VERSION 5.7 ;
  NOWIREEXTENSIONATPIN ON ;
  DIVIDERCHAR "/" ;
  BUSBITCHARS "[]" ;
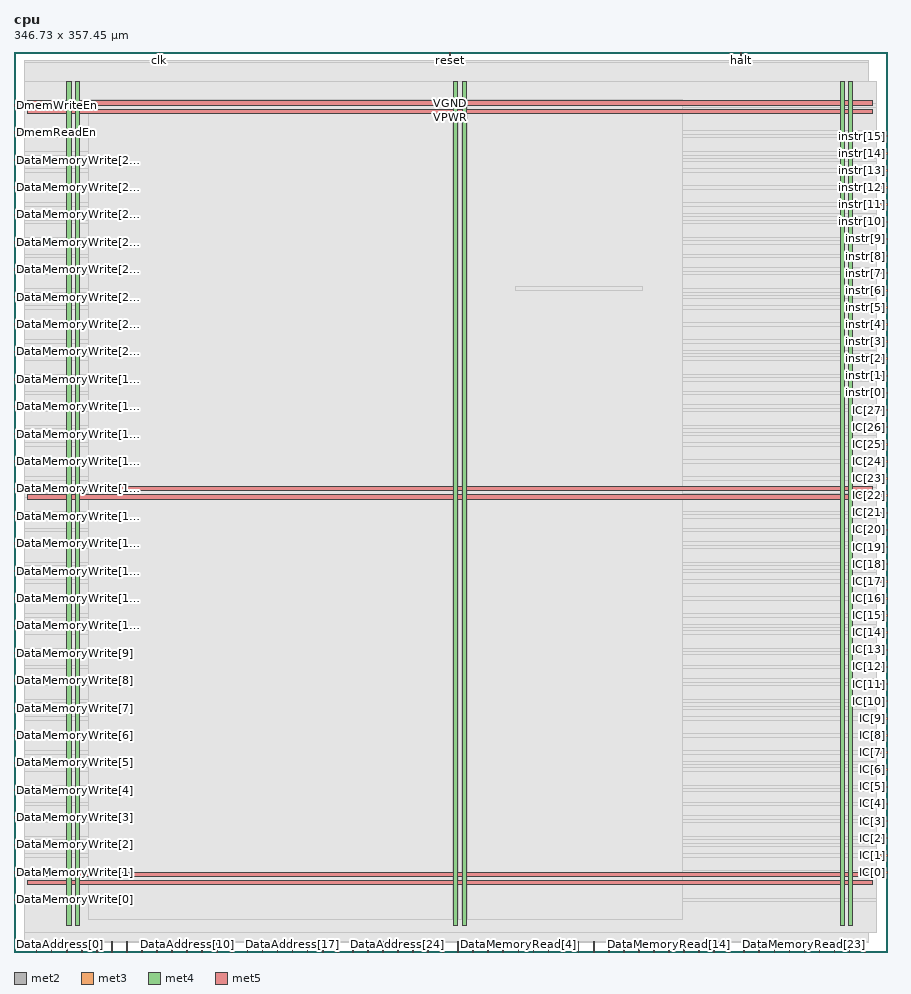
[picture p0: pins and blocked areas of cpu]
MACRO cpu
  CLASS BLOCK ;
  FOREIGN cpu ;
  ORIGIN 0.000 0.000 ;
  SIZE 346.730 BY 357.450 ;
  PIN DataAddress[0]
    DIRECTION OUTPUT ;
    USE SIGNAL ;
    ANTENNADIFFAREA 0.340600 ;
    PORT
      LAYER met2 ;
        RECT 8.830 0.000 9.110 4.000 ;
    END
  END DataAddress[0]
  PIN DataAddress[10]
    DIRECTION OUTPUT ;
    USE SIGNAL ;
    ANTENNADIFFAREA 0.340600 ;
    PORT
      LAYER met2 ;
        RECT 68.630 0.000 68.910 4.000 ;
    END
  END DataAddress[10]
  PIN DataAddress[11]
    DIRECTION OUTPUT ;
    USE SIGNAL ;
    ANTENNADIFFAREA 0.340600 ;
    PORT
      LAYER met2 ;
        RECT 74.610 0.000 74.890 4.000 ;
    END
  END DataAddress[11]
  PIN DataAddress[12]
    DIRECTION OUTPUT ;
    USE SIGNAL ;
    ANTENNADIFFAREA 0.340600 ;
    PORT
      LAYER met2 ;
        RECT 80.590 0.000 80.870 4.000 ;
    END
  END DataAddress[12]
  PIN DataAddress[13]
    DIRECTION OUTPUT ;
    USE SIGNAL ;
    ANTENNADIFFAREA 0.340600 ;
    PORT
      LAYER met2 ;
        RECT 86.570 0.000 86.850 4.000 ;
    END
  END DataAddress[13]
  PIN DataAddress[14]
    DIRECTION OUTPUT ;
    USE SIGNAL ;
    ANTENNADIFFAREA 0.340600 ;
    PORT
      LAYER met2 ;
        RECT 92.550 0.000 92.830 4.000 ;
    END
  END DataAddress[14]
  PIN DataAddress[15]
    DIRECTION OUTPUT ;
    USE SIGNAL ;
    ANTENNADIFFAREA 0.340600 ;
    PORT
      LAYER met2 ;
        RECT 98.530 0.000 98.810 4.000 ;
    END
  END DataAddress[15]
  PIN DataAddress[16]
    DIRECTION OUTPUT ;
    USE SIGNAL ;
    ANTENNADIFFAREA 0.340600 ;
    PORT
      LAYER met2 ;
        RECT 104.510 0.000 104.790 4.000 ;
    END
  END DataAddress[16]
  PIN DataAddress[17]
    DIRECTION OUTPUT ;
    USE SIGNAL ;
    ANTENNADIFFAREA 0.340600 ;
    PORT
      LAYER met2 ;
        RECT 110.490 0.000 110.770 4.000 ;
    END
  END DataAddress[17]
  PIN DataAddress[18]
    DIRECTION OUTPUT ;
    USE SIGNAL ;
    ANTENNADIFFAREA 0.340600 ;
    PORT
      LAYER met2 ;
        RECT 116.470 0.000 116.750 4.000 ;
    END
  END DataAddress[18]
  PIN DataAddress[19]
    DIRECTION OUTPUT ;
    USE SIGNAL ;
    ANTENNADIFFAREA 0.340600 ;
    PORT
      LAYER met2 ;
        RECT 122.450 0.000 122.730 4.000 ;
    END
  END DataAddress[19]
  PIN DataAddress[1]
    DIRECTION OUTPUT ;
    USE SIGNAL ;
    ANTENNADIFFAREA 0.340600 ;
    PORT
      LAYER met2 ;
        RECT 14.810 0.000 15.090 4.000 ;
    END
  END DataAddress[1]
  PIN DataAddress[20]
    DIRECTION OUTPUT ;
    USE SIGNAL ;
    ANTENNADIFFAREA 0.340600 ;
    PORT
      LAYER met2 ;
        RECT 128.430 0.000 128.710 4.000 ;
    END
  END DataAddress[20]
  PIN DataAddress[21]
    DIRECTION OUTPUT ;
    USE SIGNAL ;
    ANTENNADIFFAREA 0.340600 ;
    PORT
      LAYER met2 ;
        RECT 134.410 0.000 134.690 4.000 ;
    END
  END DataAddress[21]
  PIN DataAddress[22]
    DIRECTION OUTPUT ;
    USE SIGNAL ;
    ANTENNADIFFAREA 0.340600 ;
    PORT
      LAYER met2 ;
        RECT 140.390 0.000 140.670 4.000 ;
    END
  END DataAddress[22]
  PIN DataAddress[23]
    DIRECTION OUTPUT ;
    USE SIGNAL ;
    ANTENNADIFFAREA 0.340600 ;
    PORT
      LAYER met2 ;
        RECT 146.370 0.000 146.650 4.000 ;
    END
  END DataAddress[23]
  PIN DataAddress[24]
    DIRECTION OUTPUT ;
    USE SIGNAL ;
    ANTENNADIFFAREA 0.340600 ;
    PORT
      LAYER met2 ;
        RECT 152.350 0.000 152.630 4.000 ;
    END
  END DataAddress[24]
  PIN DataAddress[25]
    DIRECTION OUTPUT ;
    USE SIGNAL ;
    ANTENNADIFFAREA 0.340600 ;
    PORT
      LAYER met2 ;
        RECT 158.330 0.000 158.610 4.000 ;
    END
  END DataAddress[25]
  PIN DataAddress[26]
    DIRECTION OUTPUT ;
    USE SIGNAL ;
    ANTENNADIFFAREA 0.340600 ;
    PORT
      LAYER met2 ;
        RECT 164.310 0.000 164.590 4.000 ;
    END
  END DataAddress[26]
  PIN DataAddress[27]
    DIRECTION OUTPUT ;
    USE SIGNAL ;
    ANTENNADIFFAREA 0.340600 ;
    PORT
      LAYER met2 ;
        RECT 170.290 0.000 170.570 4.000 ;
    END
  END DataAddress[27]
  PIN DataAddress[2]
    DIRECTION OUTPUT ;
    USE SIGNAL ;
    ANTENNADIFFAREA 0.340600 ;
    PORT
      LAYER met2 ;
        RECT 20.790 0.000 21.070 4.000 ;
    END
  END DataAddress[2]
  PIN DataAddress[3]
    DIRECTION OUTPUT ;
    USE SIGNAL ;
    ANTENNADIFFAREA 0.340600 ;
    PORT
      LAYER met2 ;
        RECT 26.770 0.000 27.050 4.000 ;
    END
  END DataAddress[3]
  PIN DataAddress[4]
    DIRECTION OUTPUT ;
    USE SIGNAL ;
    ANTENNADIFFAREA 0.340600 ;
    PORT
      LAYER met2 ;
        RECT 32.750 0.000 33.030 4.000 ;
    END
  END DataAddress[4]
  PIN DataAddress[5]
    DIRECTION OUTPUT ;
    USE SIGNAL ;
    ANTENNADIFFAREA 0.340600 ;
    PORT
      LAYER met2 ;
        RECT 38.730 0.000 39.010 4.000 ;
    END
  END DataAddress[5]
  PIN DataAddress[6]
    DIRECTION OUTPUT ;
    USE SIGNAL ;
    ANTENNADIFFAREA 0.340600 ;
    PORT
      LAYER met2 ;
        RECT 44.710 0.000 44.990 4.000 ;
    END
  END DataAddress[6]
  PIN DataAddress[7]
    DIRECTION OUTPUT ;
    USE SIGNAL ;
    ANTENNADIFFAREA 0.340600 ;
    PORT
      LAYER met2 ;
        RECT 50.690 0.000 50.970 4.000 ;
    END
  END DataAddress[7]
  PIN DataAddress[8]
    DIRECTION OUTPUT ;
    USE SIGNAL ;
    ANTENNADIFFAREA 0.340600 ;
    PORT
      LAYER met2 ;
        RECT 56.670 0.000 56.950 4.000 ;
    END
  END DataAddress[8]
  PIN DataAddress[9]
    DIRECTION OUTPUT ;
    USE SIGNAL ;
    ANTENNADIFFAREA 0.340600 ;
    PORT
      LAYER met2 ;
        RECT 62.650 0.000 62.930 4.000 ;
    END
  END DataAddress[9]
  PIN DataMemoryRead[0]
    DIRECTION INPUT ;
    USE SIGNAL ;
    ANTENNAGATEAREA 0.196500 ;
    PORT
      LAYER met2 ;
        RECT 176.270 0.000 176.550 4.000 ;
    END
  END DataMemoryRead[0]
  PIN DataMemoryRead[10]
    DIRECTION INPUT ;
    USE SIGNAL ;
    ANTENNAGATEAREA 0.196500 ;
    PORT
      LAYER met2 ;
        RECT 236.070 0.000 236.350 4.000 ;
    END
  END DataMemoryRead[10]
  PIN DataMemoryRead[11]
    DIRECTION INPUT ;
    USE SIGNAL ;
    ANTENNAGATEAREA 0.213000 ;
    PORT
      LAYER met2 ;
        RECT 242.050 0.000 242.330 4.000 ;
    END
  END DataMemoryRead[11]
  PIN DataMemoryRead[12]
    DIRECTION INPUT ;
    USE SIGNAL ;
    ANTENNAGATEAREA 0.213000 ;
    PORT
      LAYER met2 ;
        RECT 248.030 0.000 248.310 4.000 ;
    END
  END DataMemoryRead[12]
  PIN DataMemoryRead[13]
    DIRECTION INPUT ;
    USE SIGNAL ;
    ANTENNAGATEAREA 0.213000 ;
    PORT
      LAYER met2 ;
        RECT 254.010 0.000 254.290 4.000 ;
    END
  END DataMemoryRead[13]
  PIN DataMemoryRead[14]
    DIRECTION INPUT ;
    USE SIGNAL ;
    ANTENNAGATEAREA 0.213000 ;
    PORT
      LAYER met2 ;
        RECT 259.990 0.000 260.270 4.000 ;
    END
  END DataMemoryRead[14]
  PIN DataMemoryRead[15]
    DIRECTION INPUT ;
    USE SIGNAL ;
    ANTENNAGATEAREA 0.213000 ;
    PORT
      LAYER met2 ;
        RECT 265.970 0.000 266.250 4.000 ;
    END
  END DataMemoryRead[15]
  PIN DataMemoryRead[16]
    DIRECTION INPUT ;
    USE SIGNAL ;
    ANTENNAGATEAREA 0.213000 ;
    PORT
      LAYER met2 ;
        RECT 271.950 0.000 272.230 4.000 ;
    END
  END DataMemoryRead[16]
  PIN DataMemoryRead[17]
    DIRECTION INPUT ;
    USE SIGNAL ;
    ANTENNAGATEAREA 0.213000 ;
    PORT
      LAYER met2 ;
        RECT 277.930 0.000 278.210 4.000 ;
    END
  END DataMemoryRead[17]
  PIN DataMemoryRead[18]
    DIRECTION INPUT ;
    USE SIGNAL ;
    ANTENNAGATEAREA 0.213000 ;
    PORT
      LAYER met2 ;
        RECT 283.910 0.000 284.190 4.000 ;
    END
  END DataMemoryRead[18]
  PIN DataMemoryRead[19]
    DIRECTION INPUT ;
    USE SIGNAL ;
    ANTENNAGATEAREA 0.213000 ;
    PORT
      LAYER met2 ;
        RECT 289.890 0.000 290.170 4.000 ;
    END
  END DataMemoryRead[19]
  PIN DataMemoryRead[1]
    DIRECTION INPUT ;
    USE SIGNAL ;
    ANTENNAGATEAREA 0.196500 ;
    PORT
      LAYER met2 ;
        RECT 182.250 0.000 182.530 4.000 ;
    END
  END DataMemoryRead[1]
  PIN DataMemoryRead[20]
    DIRECTION INPUT ;
    USE SIGNAL ;
    ANTENNAGATEAREA 0.196500 ;
    PORT
      LAYER met2 ;
        RECT 295.870 0.000 296.150 4.000 ;
    END
  END DataMemoryRead[20]
  PIN DataMemoryRead[21]
    DIRECTION INPUT ;
    USE SIGNAL ;
    ANTENNAGATEAREA 0.196500 ;
    PORT
      LAYER met2 ;
        RECT 301.850 0.000 302.130 4.000 ;
    END
  END DataMemoryRead[21]
  PIN DataMemoryRead[22]
    DIRECTION INPUT ;
    USE SIGNAL ;
    ANTENNAGATEAREA 0.196500 ;
    PORT
      LAYER met2 ;
        RECT 307.830 0.000 308.110 4.000 ;
    END
  END DataMemoryRead[22]
  PIN DataMemoryRead[23]
    DIRECTION INPUT ;
    USE SIGNAL ;
    ANTENNAGATEAREA 0.196500 ;
    PORT
      LAYER met2 ;
        RECT 313.810 0.000 314.090 4.000 ;
    END
  END DataMemoryRead[23]
  PIN DataMemoryRead[24]
    DIRECTION INPUT ;
    USE SIGNAL ;
    ANTENNAGATEAREA 0.196500 ;
    PORT
      LAYER met2 ;
        RECT 319.790 0.000 320.070 4.000 ;
    END
  END DataMemoryRead[24]
  PIN DataMemoryRead[25]
    DIRECTION INPUT ;
    USE SIGNAL ;
    ANTENNAGATEAREA 0.126000 ;
    PORT
      LAYER met2 ;
        RECT 325.770 0.000 326.050 4.000 ;
    END
  END DataMemoryRead[25]
  PIN DataMemoryRead[26]
    DIRECTION INPUT ;
    USE SIGNAL ;
    ANTENNAGATEAREA 0.213000 ;
    PORT
      LAYER met2 ;
        RECT 331.750 0.000 332.030 4.000 ;
    END
  END DataMemoryRead[26]
  PIN DataMemoryRead[27]
    DIRECTION INPUT ;
    USE SIGNAL ;
    ANTENNAGATEAREA 0.126000 ;
    PORT
      LAYER met2 ;
        RECT 337.730 0.000 338.010 4.000 ;
    END
  END DataMemoryRead[27]
  PIN DataMemoryRead[2]
    DIRECTION INPUT ;
    USE SIGNAL ;
    ANTENNAGATEAREA 0.196500 ;
    PORT
      LAYER met2 ;
        RECT 188.230 0.000 188.510 4.000 ;
    END
  END DataMemoryRead[2]
  PIN DataMemoryRead[3]
    DIRECTION INPUT ;
    USE SIGNAL ;
    ANTENNAGATEAREA 0.196500 ;
    PORT
      LAYER met2 ;
        RECT 194.210 0.000 194.490 4.000 ;
    END
  END DataMemoryRead[3]
  PIN DataMemoryRead[4]
    DIRECTION INPUT ;
    USE SIGNAL ;
    ANTENNAGATEAREA 0.196500 ;
    PORT
      LAYER met2 ;
        RECT 200.190 0.000 200.470 4.000 ;
    END
  END DataMemoryRead[4]
  PIN DataMemoryRead[5]
    DIRECTION INPUT ;
    USE SIGNAL ;
    ANTENNAGATEAREA 0.196500 ;
    PORT
      LAYER met2 ;
        RECT 206.170 0.000 206.450 4.000 ;
    END
  END DataMemoryRead[5]
  PIN DataMemoryRead[6]
    DIRECTION INPUT ;
    USE SIGNAL ;
    ANTENNAGATEAREA 0.196500 ;
    PORT
      LAYER met2 ;
        RECT 212.150 0.000 212.430 4.000 ;
    END
  END DataMemoryRead[6]
  PIN DataMemoryRead[7]
    DIRECTION INPUT ;
    USE SIGNAL ;
    ANTENNAGATEAREA 0.196500 ;
    PORT
      LAYER met2 ;
        RECT 218.130 0.000 218.410 4.000 ;
    END
  END DataMemoryRead[7]
  PIN DataMemoryRead[8]
    DIRECTION INPUT ;
    USE SIGNAL ;
    ANTENNAGATEAREA 0.196500 ;
    PORT
      LAYER met2 ;
        RECT 224.110 0.000 224.390 4.000 ;
    END
  END DataMemoryRead[8]
  PIN DataMemoryRead[9]
    DIRECTION INPUT ;
    USE SIGNAL ;
    ANTENNAGATEAREA 0.196500 ;
    PORT
      LAYER met2 ;
        RECT 230.090 0.000 230.370 4.000 ;
    END
  END DataMemoryRead[9]
  PIN DataMemoryWrite[0]
    DIRECTION OUTPUT ;
    USE SIGNAL ;
    ANTENNADIFFAREA 0.340600 ;
    PORT
      LAYER met3 ;
        RECT 0.000 20.440 4.000 21.040 ;
    END
  END DataMemoryWrite[0]
  PIN DataMemoryWrite[10]
    DIRECTION OUTPUT ;
    USE SIGNAL ;
    ANTENNADIFFAREA 0.340600 ;
    PORT
      LAYER met3 ;
        RECT 0.000 129.240 4.000 129.840 ;
    END
  END DataMemoryWrite[10]
  PIN DataMemoryWrite[11]
    DIRECTION OUTPUT ;
    USE SIGNAL ;
    ANTENNADIFFAREA 0.340600 ;
    PORT
      LAYER met3 ;
        RECT 0.000 140.120 4.000 140.720 ;
    END
  END DataMemoryWrite[11]
  PIN DataMemoryWrite[12]
    DIRECTION OUTPUT ;
    USE SIGNAL ;
    ANTENNADIFFAREA 0.340600 ;
    PORT
      LAYER met3 ;
        RECT 0.000 151.000 4.000 151.600 ;
    END
  END DataMemoryWrite[12]
  PIN DataMemoryWrite[13]
    DIRECTION OUTPUT ;
    USE SIGNAL ;
    ANTENNADIFFAREA 0.340600 ;
    PORT
      LAYER met3 ;
        RECT 0.000 161.880 4.000 162.480 ;
    END
  END DataMemoryWrite[13]
  PIN DataMemoryWrite[14]
    DIRECTION OUTPUT ;
    USE SIGNAL ;
    ANTENNADIFFAREA 0.340600 ;
    PORT
      LAYER met3 ;
        RECT 0.000 172.760 4.000 173.360 ;
    END
  END DataMemoryWrite[14]
  PIN DataMemoryWrite[15]
    DIRECTION OUTPUT ;
    USE SIGNAL ;
    ANTENNADIFFAREA 0.340600 ;
    PORT
      LAYER met3 ;
        RECT 0.000 183.640 4.000 184.240 ;
    END
  END DataMemoryWrite[15]
  PIN DataMemoryWrite[16]
    DIRECTION OUTPUT ;
    USE SIGNAL ;
    ANTENNADIFFAREA 0.340600 ;
    PORT
      LAYER met3 ;
        RECT 0.000 194.520 4.000 195.120 ;
    END
  END DataMemoryWrite[16]
  PIN DataMemoryWrite[17]
    DIRECTION OUTPUT ;
    USE SIGNAL ;
    ANTENNADIFFAREA 0.340600 ;
    PORT
      LAYER met3 ;
        RECT 0.000 205.400 4.000 206.000 ;
    END
  END DataMemoryWrite[17]
  PIN DataMemoryWrite[18]
    DIRECTION OUTPUT ;
    USE SIGNAL ;
    ANTENNADIFFAREA 0.340600 ;
    PORT
      LAYER met3 ;
        RECT 0.000 216.280 4.000 216.880 ;
    END
  END DataMemoryWrite[18]
  PIN DataMemoryWrite[19]
    DIRECTION OUTPUT ;
    USE SIGNAL ;
    ANTENNADIFFAREA 0.340600 ;
    PORT
      LAYER met3 ;
        RECT 0.000 227.160 4.000 227.760 ;
    END
  END DataMemoryWrite[19]
  PIN DataMemoryWrite[1]
    DIRECTION OUTPUT ;
    USE SIGNAL ;
    ANTENNADIFFAREA 0.340600 ;
    PORT
      LAYER met3 ;
        RECT 0.000 31.320 4.000 31.920 ;
    END
  END DataMemoryWrite[1]
  PIN DataMemoryWrite[20]
    DIRECTION OUTPUT ;
    USE SIGNAL ;
    ANTENNADIFFAREA 0.340600 ;
    PORT
      LAYER met3 ;
        RECT 0.000 238.040 4.000 238.640 ;
    END
  END DataMemoryWrite[20]
  PIN DataMemoryWrite[21]
    DIRECTION OUTPUT ;
    USE SIGNAL ;
    ANTENNADIFFAREA 0.340600 ;
    PORT
      LAYER met3 ;
        RECT 0.000 248.920 4.000 249.520 ;
    END
  END DataMemoryWrite[21]
  PIN DataMemoryWrite[22]
    DIRECTION OUTPUT ;
    USE SIGNAL ;
    ANTENNADIFFAREA 0.340600 ;
    PORT
      LAYER met3 ;
        RECT 0.000 259.800 4.000 260.400 ;
    END
  END DataMemoryWrite[22]
  PIN DataMemoryWrite[23]
    DIRECTION OUTPUT ;
    USE SIGNAL ;
    ANTENNADIFFAREA 0.340600 ;
    PORT
      LAYER met3 ;
        RECT 0.000 270.680 4.000 271.280 ;
    END
  END DataMemoryWrite[23]
  PIN DataMemoryWrite[24]
    DIRECTION OUTPUT ;
    USE SIGNAL ;
    ANTENNADIFFAREA 0.340600 ;
    PORT
      LAYER met3 ;
        RECT 0.000 281.560 4.000 282.160 ;
    END
  END DataMemoryWrite[24]
  PIN DataMemoryWrite[25]
    DIRECTION OUTPUT ;
    USE SIGNAL ;
    ANTENNADIFFAREA 0.340600 ;
    PORT
      LAYER met3 ;
        RECT 0.000 292.440 4.000 293.040 ;
    END
  END DataMemoryWrite[25]
  PIN DataMemoryWrite[26]
    DIRECTION OUTPUT ;
    USE SIGNAL ;
    ANTENNADIFFAREA 0.340600 ;
    PORT
      LAYER met3 ;
        RECT 0.000 303.320 4.000 303.920 ;
    END
  END DataMemoryWrite[26]
  PIN DataMemoryWrite[27]
    DIRECTION OUTPUT ;
    USE SIGNAL ;
    ANTENNADIFFAREA 0.340600 ;
    PORT
      LAYER met3 ;
        RECT 0.000 314.200 4.000 314.800 ;
    END
  END DataMemoryWrite[27]
  PIN DataMemoryWrite[2]
    DIRECTION OUTPUT ;
    USE SIGNAL ;
    ANTENNADIFFAREA 0.340600 ;
    PORT
      LAYER met3 ;
        RECT 0.000 42.200 4.000 42.800 ;
    END
  END DataMemoryWrite[2]
  PIN DataMemoryWrite[3]
    DIRECTION OUTPUT ;
    USE SIGNAL ;
    ANTENNADIFFAREA 0.340600 ;
    PORT
      LAYER met3 ;
        RECT 0.000 53.080 4.000 53.680 ;
    END
  END DataMemoryWrite[3]
  PIN DataMemoryWrite[4]
    DIRECTION OUTPUT ;
    USE SIGNAL ;
    ANTENNADIFFAREA 0.340600 ;
    PORT
      LAYER met3 ;
        RECT 0.000 63.960 4.000 64.560 ;
    END
  END DataMemoryWrite[4]
  PIN DataMemoryWrite[5]
    DIRECTION OUTPUT ;
    USE SIGNAL ;
    ANTENNADIFFAREA 0.340600 ;
    PORT
      LAYER met3 ;
        RECT 0.000 74.840 4.000 75.440 ;
    END
  END DataMemoryWrite[5]
  PIN DataMemoryWrite[6]
    DIRECTION OUTPUT ;
    USE SIGNAL ;
    ANTENNADIFFAREA 0.340600 ;
    PORT
      LAYER met3 ;
        RECT 0.000 85.720 4.000 86.320 ;
    END
  END DataMemoryWrite[6]
  PIN DataMemoryWrite[7]
    DIRECTION OUTPUT ;
    USE SIGNAL ;
    ANTENNADIFFAREA 0.340600 ;
    PORT
      LAYER met3 ;
        RECT 0.000 96.600 4.000 97.200 ;
    END
  END DataMemoryWrite[7]
  PIN DataMemoryWrite[8]
    DIRECTION OUTPUT ;
    USE SIGNAL ;
    ANTENNADIFFAREA 0.340600 ;
    PORT
      LAYER met3 ;
        RECT 0.000 107.480 4.000 108.080 ;
    END
  END DataMemoryWrite[8]
  PIN DataMemoryWrite[9]
    DIRECTION OUTPUT ;
    USE SIGNAL ;
    ANTENNADIFFAREA 0.340600 ;
    PORT
      LAYER met3 ;
        RECT 0.000 118.360 4.000 118.960 ;
    END
  END DataMemoryWrite[9]
  PIN DmemReadEn
    DIRECTION OUTPUT ;
    USE SIGNAL ;
    ANTENNADIFFAREA 0.340600 ;
    PORT
      LAYER met3 ;
        RECT 0.000 325.080 4.000 325.680 ;
    END
  END DmemReadEn
  PIN DmemWriteEn
    DIRECTION OUTPUT ;
    USE SIGNAL ;
    ANTENNADIFFAREA 0.340600 ;
    PORT
      LAYER met3 ;
        RECT 0.000 335.960 4.000 336.560 ;
    END
  END DmemWriteEn
  PIN IC[0]
    DIRECTION OUTPUT ;
    USE SIGNAL ;
    PORT
      LAYER met3 ;
        RECT 342.730 31.320 346.730 31.920 ;
    END
  END IC[0]
  PIN IC[10]
    DIRECTION OUTPUT ;
    USE SIGNAL ;
    ANTENNADIFFAREA 0.340600 ;
    PORT
      LAYER met3 ;
        RECT 342.730 99.320 346.730 99.920 ;
    END
  END IC[10]
  PIN IC[11]
    DIRECTION OUTPUT ;
    USE SIGNAL ;
    ANTENNADIFFAREA 0.340600 ;
    PORT
      LAYER met3 ;
        RECT 342.730 106.120 346.730 106.720 ;
    END
  END IC[11]
  PIN IC[12]
    DIRECTION OUTPUT ;
    USE SIGNAL ;
    ANTENNADIFFAREA 0.340600 ;
    PORT
      LAYER met3 ;
        RECT 342.730 112.920 346.730 113.520 ;
    END
  END IC[12]
  PIN IC[13]
    DIRECTION OUTPUT ;
    USE SIGNAL ;
    ANTENNADIFFAREA 0.340600 ;
    PORT
      LAYER met3 ;
        RECT 342.730 119.720 346.730 120.320 ;
    END
  END IC[13]
  PIN IC[14]
    DIRECTION OUTPUT ;
    USE SIGNAL ;
    ANTENNADIFFAREA 0.340600 ;
    PORT
      LAYER met3 ;
        RECT 342.730 126.520 346.730 127.120 ;
    END
  END IC[14]
  PIN IC[15]
    DIRECTION OUTPUT ;
    USE SIGNAL ;
    ANTENNADIFFAREA 0.340600 ;
    PORT
      LAYER met3 ;
        RECT 342.730 133.320 346.730 133.920 ;
    END
  END IC[15]
  PIN IC[16]
    DIRECTION OUTPUT ;
    USE SIGNAL ;
    ANTENNADIFFAREA 0.340600 ;
    PORT
      LAYER met3 ;
        RECT 342.730 140.120 346.730 140.720 ;
    END
  END IC[16]
  PIN IC[17]
    DIRECTION OUTPUT ;
    USE SIGNAL ;
    ANTENNADIFFAREA 0.340600 ;
    PORT
      LAYER met3 ;
        RECT 342.730 146.920 346.730 147.520 ;
    END
  END IC[17]
  PIN IC[18]
    DIRECTION OUTPUT ;
    USE SIGNAL ;
    ANTENNADIFFAREA 0.340600 ;
    PORT
      LAYER met3 ;
        RECT 342.730 153.720 346.730 154.320 ;
    END
  END IC[18]
  PIN IC[19]
    DIRECTION OUTPUT ;
    USE SIGNAL ;
    ANTENNADIFFAREA 0.340600 ;
    PORT
      LAYER met3 ;
        RECT 342.730 160.520 346.730 161.120 ;
    END
  END IC[19]
  PIN IC[1]
    DIRECTION OUTPUT ;
    USE SIGNAL ;
    ANTENNADIFFAREA 0.340600 ;
    PORT
      LAYER met3 ;
        RECT 342.730 38.120 346.730 38.720 ;
    END
  END IC[1]
  PIN IC[20]
    DIRECTION OUTPUT ;
    USE SIGNAL ;
    ANTENNADIFFAREA 0.340600 ;
    PORT
      LAYER met3 ;
        RECT 342.730 167.320 346.730 167.920 ;
    END
  END IC[20]
  PIN IC[21]
    DIRECTION OUTPUT ;
    USE SIGNAL ;
    ANTENNADIFFAREA 0.340600 ;
    PORT
      LAYER met3 ;
        RECT 342.730 174.120 346.730 174.720 ;
    END
  END IC[21]
  PIN IC[22]
    DIRECTION OUTPUT ;
    USE SIGNAL ;
    ANTENNADIFFAREA 0.340600 ;
    PORT
      LAYER met3 ;
        RECT 342.730 180.920 346.730 181.520 ;
    END
  END IC[22]
  PIN IC[23]
    DIRECTION OUTPUT ;
    USE SIGNAL ;
    ANTENNADIFFAREA 0.340600 ;
    PORT
      LAYER met3 ;
        RECT 342.730 187.720 346.730 188.320 ;
    END
  END IC[23]
  PIN IC[24]
    DIRECTION OUTPUT ;
    USE SIGNAL ;
    ANTENNADIFFAREA 0.340600 ;
    PORT
      LAYER met3 ;
        RECT 342.730 194.520 346.730 195.120 ;
    END
  END IC[24]
  PIN IC[25]
    DIRECTION OUTPUT ;
    USE SIGNAL ;
    ANTENNADIFFAREA 0.340600 ;
    PORT
      LAYER met3 ;
        RECT 342.730 201.320 346.730 201.920 ;
    END
  END IC[25]
  PIN IC[26]
    DIRECTION OUTPUT ;
    USE SIGNAL ;
    ANTENNADIFFAREA 0.340600 ;
    PORT
      LAYER met3 ;
        RECT 342.730 208.120 346.730 208.720 ;
    END
  END IC[26]
  PIN IC[27]
    DIRECTION OUTPUT ;
    USE SIGNAL ;
    ANTENNADIFFAREA 0.340600 ;
    PORT
      LAYER met3 ;
        RECT 342.730 214.920 346.730 215.520 ;
    END
  END IC[27]
  PIN IC[2]
    DIRECTION OUTPUT ;
    USE SIGNAL ;
    ANTENNADIFFAREA 0.340600 ;
    PORT
      LAYER met3 ;
        RECT 342.730 44.920 346.730 45.520 ;
    END
  END IC[2]
  PIN IC[3]
    DIRECTION OUTPUT ;
    USE SIGNAL ;
    ANTENNADIFFAREA 0.340600 ;
    PORT
      LAYER met3 ;
        RECT 342.730 51.720 346.730 52.320 ;
    END
  END IC[3]
  PIN IC[4]
    DIRECTION OUTPUT ;
    USE SIGNAL ;
    ANTENNADIFFAREA 0.340600 ;
    PORT
      LAYER met3 ;
        RECT 342.730 58.520 346.730 59.120 ;
    END
  END IC[4]
  PIN IC[5]
    DIRECTION OUTPUT ;
    USE SIGNAL ;
    ANTENNADIFFAREA 0.340600 ;
    PORT
      LAYER met3 ;
        RECT 342.730 65.320 346.730 65.920 ;
    END
  END IC[5]
  PIN IC[6]
    DIRECTION OUTPUT ;
    USE SIGNAL ;
    ANTENNADIFFAREA 0.340600 ;
    PORT
      LAYER met3 ;
        RECT 342.730 72.120 346.730 72.720 ;
    END
  END IC[6]
  PIN IC[7]
    DIRECTION OUTPUT ;
    USE SIGNAL ;
    ANTENNADIFFAREA 0.340600 ;
    PORT
      LAYER met3 ;
        RECT 342.730 78.920 346.730 79.520 ;
    END
  END IC[7]
  PIN IC[8]
    DIRECTION OUTPUT ;
    USE SIGNAL ;
    ANTENNADIFFAREA 0.340600 ;
    PORT
      LAYER met3 ;
        RECT 342.730 85.720 346.730 86.320 ;
    END
  END IC[8]
  PIN IC[9]
    DIRECTION OUTPUT ;
    USE SIGNAL ;
    ANTENNADIFFAREA 0.340600 ;
    PORT
      LAYER met3 ;
        RECT 342.730 92.520 346.730 93.120 ;
    END
  END IC[9]
  PIN VGND
    DIRECTION INOUT ;
    USE GROUND ;
    PORT
      LAYER met4 ;
        RECT 24.340 10.640 25.940 345.680 ;
    END
    PORT
      LAYER met4 ;
        RECT 177.940 10.640 179.540 345.680 ;
    END
    PORT
      LAYER met4 ;
        RECT 331.540 10.640 333.140 345.680 ;
    END
    PORT
      LAYER met5 ;
        RECT 5.280 30.030 341.100 31.630 ;
    END
    PORT
      LAYER met5 ;
        RECT 5.280 183.210 341.100 184.810 ;
    END
    PORT
      LAYER met5 ;
        RECT 5.280 336.390 341.100 337.990 ;
    END
  END VGND
  PIN VPWR
    DIRECTION INOUT ;
    USE POWER ;
    PORT
      LAYER met4 ;
        RECT 21.040 10.640 22.640 345.680 ;
    END
    PORT
      LAYER met4 ;
        RECT 174.640 10.640 176.240 345.680 ;
    END
    PORT
      LAYER met4 ;
        RECT 328.240 10.640 329.840 345.680 ;
    END
    PORT
      LAYER met5 ;
        RECT 5.280 26.730 341.100 28.330 ;
    END
    PORT
      LAYER met5 ;
        RECT 5.280 179.910 341.100 181.510 ;
    END
    PORT
      LAYER met5 ;
        RECT 5.280 333.090 341.100 334.690 ;
    END
  END VPWR
  PIN clk
    DIRECTION INPUT ;
    USE SIGNAL ;
    ANTENNAGATEAREA 0.852000 ;
    PORT
      LAYER met2 ;
        RECT 57.590 353.450 57.870 357.450 ;
    END
  END clk
  PIN halt
    DIRECTION OUTPUT ;
    USE SIGNAL ;
    ANTENNADIFFAREA 0.340600 ;
    PORT
      LAYER met2 ;
        RECT 288.510 353.450 288.790 357.450 ;
    END
  END halt
  PIN instr[0]
    DIRECTION INPUT ;
    USE SIGNAL ;
    ANTENNAGATEAREA 0.495000 ;
    PORT
      LAYER met3 ;
        RECT 342.730 221.720 346.730 222.320 ;
    END
  END instr[0]
  PIN instr[10]
    DIRECTION INPUT ;
    USE SIGNAL ;
    ANTENNAGATEAREA 0.247500 ;
    PORT
      LAYER met3 ;
        RECT 342.730 289.720 346.730 290.320 ;
    END
  END instr[10]
  PIN instr[11]
    DIRECTION INPUT ;
    USE SIGNAL ;
    ANTENNAGATEAREA 0.213000 ;
    PORT
      LAYER met3 ;
        RECT 342.730 296.520 346.730 297.120 ;
    END
  END instr[11]
  PIN instr[12]
    DIRECTION INPUT ;
    USE SIGNAL ;
    ANTENNAGATEAREA 0.213000 ;
    PORT
      LAYER met3 ;
        RECT 342.730 303.320 346.730 303.920 ;
    END
  END instr[12]
  PIN instr[13]
    DIRECTION INPUT ;
    USE SIGNAL ;
    ANTENNAGATEAREA 0.213000 ;
    PORT
      LAYER met3 ;
        RECT 342.730 310.120 346.730 310.720 ;
    END
  END instr[13]
  PIN instr[14]
    DIRECTION INPUT ;
    USE SIGNAL ;
    ANTENNAGATEAREA 0.990000 ;
    PORT
      LAYER met3 ;
        RECT 342.730 316.920 346.730 317.520 ;
    END
  END instr[14]
  PIN instr[15]
    DIRECTION INPUT ;
    USE SIGNAL ;
    PORT
      LAYER met3 ;
        RECT 342.730 323.720 346.730 324.320 ;
    END
  END instr[15]
  PIN instr[1]
    DIRECTION INPUT ;
    USE SIGNAL ;
    ANTENNAGATEAREA 0.495000 ;
    PORT
      LAYER met3 ;
        RECT 342.730 228.520 346.730 229.120 ;
    END
  END instr[1]
  PIN instr[2]
    DIRECTION INPUT ;
    USE SIGNAL ;
    ANTENNAGATEAREA 0.426000 ;
    PORT
      LAYER met3 ;
        RECT 342.730 235.320 346.730 235.920 ;
    END
  END instr[2]
  PIN instr[3]
    DIRECTION INPUT ;
    USE SIGNAL ;
    ANTENNAGATEAREA 0.426000 ;
    PORT
      LAYER met3 ;
        RECT 342.730 242.120 346.730 242.720 ;
    END
  END instr[3]
  PIN instr[4]
    DIRECTION INPUT ;
    USE SIGNAL ;
    ANTENNAGATEAREA 0.247500 ;
    PORT
      LAYER met3 ;
        RECT 342.730 248.920 346.730 249.520 ;
    END
  END instr[4]
  PIN instr[5]
    DIRECTION INPUT ;
    USE SIGNAL ;
    ANTENNAGATEAREA 0.247500 ;
    PORT
      LAYER met3 ;
        RECT 342.730 255.720 346.730 256.320 ;
    END
  END instr[5]
  PIN instr[6]
    DIRECTION INPUT ;
    USE SIGNAL ;
    ANTENNAGATEAREA 0.426000 ;
    PORT
      LAYER met3 ;
        RECT 342.730 262.520 346.730 263.120 ;
    END
  END instr[6]
  PIN instr[7]
    DIRECTION INPUT ;
    USE SIGNAL ;
    ANTENNAGATEAREA 0.990000 ;
    PORT
      LAYER met3 ;
        RECT 342.730 269.320 346.730 269.920 ;
    END
  END instr[7]
  PIN instr[8]
    DIRECTION INPUT ;
    USE SIGNAL ;
    ANTENNAGATEAREA 0.247500 ;
    PORT
      LAYER met3 ;
        RECT 342.730 276.120 346.730 276.720 ;
    END
  END instr[8]
  PIN instr[9]
    DIRECTION INPUT ;
    USE SIGNAL ;
    ANTENNAGATEAREA 0.495000 ;
    PORT
      LAYER met3 ;
        RECT 342.730 282.920 346.730 283.520 ;
    END
  END instr[9]
  PIN reset
    DIRECTION INPUT ;
    USE SIGNAL ;
    ANTENNAGATEAREA 0.990000 ;
    PORT
      LAYER met2 ;
        RECT 173.050 353.450 173.330 357.450 ;
    END
  END reset
  OBS
      LAYER nwell ;
        RECT 5.330 10.795 341.050 345.630 ;
      LAYER li1 ;
        RECT 5.520 10.795 340.860 345.525 ;
      LAYER met1 ;
        RECT 4.210 7.860 341.160 345.680 ;
      LAYER met2 ;
        RECT 4.230 353.170 57.310 354.010 ;
        RECT 58.150 353.170 172.770 354.010 ;
        RECT 173.610 353.170 288.230 354.010 ;
        RECT 289.070 353.170 339.390 354.010 ;
        RECT 4.230 4.280 339.390 353.170 ;
        RECT 4.230 3.670 8.550 4.280 ;
        RECT 9.390 3.670 14.530 4.280 ;
        RECT 15.370 3.670 20.510 4.280 ;
        RECT 21.350 3.670 26.490 4.280 ;
        RECT 27.330 3.670 32.470 4.280 ;
        RECT 33.310 3.670 38.450 4.280 ;
        RECT 39.290 3.670 44.430 4.280 ;
        RECT 45.270 3.670 50.410 4.280 ;
        RECT 51.250 3.670 56.390 4.280 ;
        RECT 57.230 3.670 62.370 4.280 ;
        RECT 63.210 3.670 68.350 4.280 ;
        RECT 69.190 3.670 74.330 4.280 ;
        RECT 75.170 3.670 80.310 4.280 ;
        RECT 81.150 3.670 86.290 4.280 ;
        RECT 87.130 3.670 92.270 4.280 ;
        RECT 93.110 3.670 98.250 4.280 ;
        RECT 99.090 3.670 104.230 4.280 ;
        RECT 105.070 3.670 110.210 4.280 ;
        RECT 111.050 3.670 116.190 4.280 ;
        RECT 117.030 3.670 122.170 4.280 ;
        RECT 123.010 3.670 128.150 4.280 ;
        RECT 128.990 3.670 134.130 4.280 ;
        RECT 134.970 3.670 140.110 4.280 ;
        RECT 140.950 3.670 146.090 4.280 ;
        RECT 146.930 3.670 152.070 4.280 ;
        RECT 152.910 3.670 158.050 4.280 ;
        RECT 158.890 3.670 164.030 4.280 ;
        RECT 164.870 3.670 170.010 4.280 ;
        RECT 170.850 3.670 175.990 4.280 ;
        RECT 176.830 3.670 181.970 4.280 ;
        RECT 182.810 3.670 187.950 4.280 ;
        RECT 188.790 3.670 193.930 4.280 ;
        RECT 194.770 3.670 199.910 4.280 ;
        RECT 200.750 3.670 205.890 4.280 ;
        RECT 206.730 3.670 211.870 4.280 ;
        RECT 212.710 3.670 217.850 4.280 ;
        RECT 218.690 3.670 223.830 4.280 ;
        RECT 224.670 3.670 229.810 4.280 ;
        RECT 230.650 3.670 235.790 4.280 ;
        RECT 236.630 3.670 241.770 4.280 ;
        RECT 242.610 3.670 247.750 4.280 ;
        RECT 248.590 3.670 253.730 4.280 ;
        RECT 254.570 3.670 259.710 4.280 ;
        RECT 260.550 3.670 265.690 4.280 ;
        RECT 266.530 3.670 271.670 4.280 ;
        RECT 272.510 3.670 277.650 4.280 ;
        RECT 278.490 3.670 283.630 4.280 ;
        RECT 284.470 3.670 289.610 4.280 ;
        RECT 290.450 3.670 295.590 4.280 ;
        RECT 296.430 3.670 301.570 4.280 ;
        RECT 302.410 3.670 307.550 4.280 ;
        RECT 308.390 3.670 313.530 4.280 ;
        RECT 314.370 3.670 319.510 4.280 ;
        RECT 320.350 3.670 325.490 4.280 ;
        RECT 326.330 3.670 331.470 4.280 ;
        RECT 332.310 3.670 337.450 4.280 ;
        RECT 338.290 3.670 339.390 4.280 ;
      LAYER met3 ;
        RECT 3.990 336.960 342.730 345.605 ;
        RECT 4.400 335.560 342.730 336.960 ;
        RECT 3.990 326.080 342.730 335.560 ;
        RECT 4.400 324.720 342.730 326.080 ;
        RECT 4.400 324.680 342.330 324.720 ;
        RECT 3.990 323.320 342.330 324.680 ;
        RECT 3.990 317.920 342.730 323.320 ;
        RECT 3.990 316.520 342.330 317.920 ;
        RECT 3.990 315.200 342.730 316.520 ;
        RECT 4.400 313.800 342.730 315.200 ;
        RECT 3.990 311.120 342.730 313.800 ;
        RECT 3.990 309.720 342.330 311.120 ;
        RECT 3.990 304.320 342.730 309.720 ;
        RECT 4.400 302.920 342.330 304.320 ;
        RECT 3.990 297.520 342.730 302.920 ;
        RECT 3.990 296.120 342.330 297.520 ;
        RECT 3.990 293.440 342.730 296.120 ;
        RECT 4.400 292.040 342.730 293.440 ;
        RECT 3.990 290.720 342.730 292.040 ;
        RECT 3.990 289.320 342.330 290.720 ;
        RECT 3.990 283.920 342.730 289.320 ;
        RECT 3.990 282.560 342.330 283.920 ;
        RECT 4.400 282.520 342.330 282.560 ;
        RECT 4.400 281.160 342.730 282.520 ;
        RECT 3.990 277.120 342.730 281.160 ;
        RECT 3.990 275.720 342.330 277.120 ;
        RECT 3.990 271.680 342.730 275.720 ;
        RECT 4.400 270.320 342.730 271.680 ;
        RECT 4.400 270.280 342.330 270.320 ;
        RECT 3.990 268.920 342.330 270.280 ;
        RECT 3.990 263.520 342.730 268.920 ;
        RECT 3.990 262.120 342.330 263.520 ;
        RECT 3.990 260.800 342.730 262.120 ;
        RECT 4.400 259.400 342.730 260.800 ;
        RECT 3.990 256.720 342.730 259.400 ;
        RECT 3.990 255.320 342.330 256.720 ;
        RECT 3.990 249.920 342.730 255.320 ;
        RECT 4.400 248.520 342.330 249.920 ;
        RECT 3.990 243.120 342.730 248.520 ;
        RECT 3.990 241.720 342.330 243.120 ;
        RECT 3.990 239.040 342.730 241.720 ;
        RECT 4.400 237.640 342.730 239.040 ;
        RECT 3.990 236.320 342.730 237.640 ;
        RECT 3.990 234.920 342.330 236.320 ;
        RECT 3.990 229.520 342.730 234.920 ;
        RECT 3.990 228.160 342.330 229.520 ;
        RECT 4.400 228.120 342.330 228.160 ;
        RECT 4.400 226.760 342.730 228.120 ;
        RECT 3.990 222.720 342.730 226.760 ;
        RECT 3.990 221.320 342.330 222.720 ;
        RECT 3.990 217.280 342.730 221.320 ;
        RECT 4.400 215.920 342.730 217.280 ;
        RECT 4.400 215.880 342.330 215.920 ;
        RECT 3.990 214.520 342.330 215.880 ;
        RECT 3.990 209.120 342.730 214.520 ;
        RECT 3.990 207.720 342.330 209.120 ;
        RECT 3.990 206.400 342.730 207.720 ;
        RECT 4.400 205.000 342.730 206.400 ;
        RECT 3.990 202.320 342.730 205.000 ;
        RECT 3.990 200.920 342.330 202.320 ;
        RECT 3.990 195.520 342.730 200.920 ;
        RECT 4.400 194.120 342.330 195.520 ;
        RECT 3.990 188.720 342.730 194.120 ;
        RECT 3.990 187.320 342.330 188.720 ;
        RECT 3.990 184.640 342.730 187.320 ;
        RECT 4.400 183.240 342.730 184.640 ;
        RECT 3.990 181.920 342.730 183.240 ;
        RECT 3.990 180.520 342.330 181.920 ;
        RECT 3.990 175.120 342.730 180.520 ;
        RECT 3.990 173.760 342.330 175.120 ;
        RECT 4.400 173.720 342.330 173.760 ;
        RECT 4.400 172.360 342.730 173.720 ;
        RECT 3.990 168.320 342.730 172.360 ;
        RECT 3.990 166.920 342.330 168.320 ;
        RECT 3.990 162.880 342.730 166.920 ;
        RECT 4.400 161.520 342.730 162.880 ;
        RECT 4.400 161.480 342.330 161.520 ;
        RECT 3.990 160.120 342.330 161.480 ;
        RECT 3.990 154.720 342.730 160.120 ;
        RECT 3.990 153.320 342.330 154.720 ;
        RECT 3.990 152.000 342.730 153.320 ;
        RECT 4.400 150.600 342.730 152.000 ;
        RECT 3.990 147.920 342.730 150.600 ;
        RECT 3.990 146.520 342.330 147.920 ;
        RECT 3.990 141.120 342.730 146.520 ;
        RECT 4.400 139.720 342.330 141.120 ;
        RECT 3.990 134.320 342.730 139.720 ;
        RECT 3.990 132.920 342.330 134.320 ;
        RECT 3.990 130.240 342.730 132.920 ;
        RECT 4.400 128.840 342.730 130.240 ;
        RECT 3.990 127.520 342.730 128.840 ;
        RECT 3.990 126.120 342.330 127.520 ;
        RECT 3.990 120.720 342.730 126.120 ;
        RECT 3.990 119.360 342.330 120.720 ;
        RECT 4.400 119.320 342.330 119.360 ;
        RECT 4.400 117.960 342.730 119.320 ;
        RECT 3.990 113.920 342.730 117.960 ;
        RECT 3.990 112.520 342.330 113.920 ;
        RECT 3.990 108.480 342.730 112.520 ;
        RECT 4.400 107.120 342.730 108.480 ;
        RECT 4.400 107.080 342.330 107.120 ;
        RECT 3.990 105.720 342.330 107.080 ;
        RECT 3.990 100.320 342.730 105.720 ;
        RECT 3.990 98.920 342.330 100.320 ;
        RECT 3.990 97.600 342.730 98.920 ;
        RECT 4.400 96.200 342.730 97.600 ;
        RECT 3.990 93.520 342.730 96.200 ;
        RECT 3.990 92.120 342.330 93.520 ;
        RECT 3.990 86.720 342.730 92.120 ;
        RECT 4.400 85.320 342.330 86.720 ;
        RECT 3.990 79.920 342.730 85.320 ;
        RECT 3.990 78.520 342.330 79.920 ;
        RECT 3.990 75.840 342.730 78.520 ;
        RECT 4.400 74.440 342.730 75.840 ;
        RECT 3.990 73.120 342.730 74.440 ;
        RECT 3.990 71.720 342.330 73.120 ;
        RECT 3.990 66.320 342.730 71.720 ;
        RECT 3.990 64.960 342.330 66.320 ;
        RECT 4.400 64.920 342.330 64.960 ;
        RECT 4.400 63.560 342.730 64.920 ;
        RECT 3.990 59.520 342.730 63.560 ;
        RECT 3.990 58.120 342.330 59.520 ;
        RECT 3.990 54.080 342.730 58.120 ;
        RECT 4.400 52.720 342.730 54.080 ;
        RECT 4.400 52.680 342.330 52.720 ;
        RECT 3.990 51.320 342.330 52.680 ;
        RECT 3.990 45.920 342.730 51.320 ;
        RECT 3.990 44.520 342.330 45.920 ;
        RECT 3.990 43.200 342.730 44.520 ;
        RECT 4.400 41.800 342.730 43.200 ;
        RECT 3.990 39.120 342.730 41.800 ;
        RECT 3.990 37.720 342.330 39.120 ;
        RECT 3.990 32.320 342.730 37.720 ;
        RECT 4.400 30.920 342.330 32.320 ;
        RECT 3.990 21.440 342.730 30.920 ;
        RECT 4.400 20.040 342.730 21.440 ;
        RECT 3.990 7.655 342.730 20.040 ;
      LAYER met4 ;
        RECT 29.735 13.095 174.240 338.465 ;
        RECT 176.640 13.095 177.540 338.465 ;
        RECT 179.940 13.095 265.585 338.465 ;
      LAYER met5 ;
        RECT 199.300 262.700 249.660 264.300 ;
  END
END cpu
END LIBRARY

